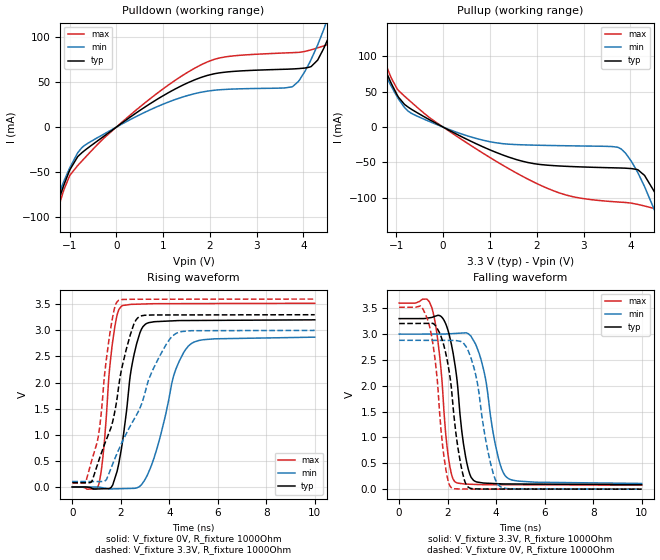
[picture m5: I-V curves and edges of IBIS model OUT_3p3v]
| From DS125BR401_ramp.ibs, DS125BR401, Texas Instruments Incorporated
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[Model]   OUT_3p3v
Model_type   Output
Polarity   Non-Inverting
Vmeas = 1.65
Vref = 0
Cref = 1pF
Rref = 1000000
|   typ   min   max
C_comp   1.124pF   1.078pF   1.193pF
[Voltage Range]   3.3   3   3.6
[Temperature Range]   25   105   -40
[Pullup Reference]   3.3   3   3.6
[Pulldown Reference]   0   0   0
[Power Clamp Reference]   3.3   3   3.6
[GND Clamp Reference]   0   0   0
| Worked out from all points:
|   slope of the pulldown table from 0 to 0.495 V, typ, clamps not added: 27.1 ohm
|   slope of the pullup table from 0 to 0.495 V, typ, clamps not added: 29.4 ohm
|   falling waveform, V_fixture 3.3V, R_fixture 1000Ohm: 20-80 % time 489ps typ, 628ps min, 396ps max; typ from 3.3 V to 0.088 V
|   rising waveform, V_fixture 0V, R_fixture 1000Ohm: 20-80 % time 569ps typ, 924ps min, 383ps max; typ from 0 V to 3.2 V
|   rising waveform, V_fixture 3.3V, R_fixture 1000Ohm: 20-80 % time 977ps typ, 1.62ns min, 558ps max; typ from 0.086 V to 3.3 V
|   falling waveform, V_fixture 0V, R_fixture 1000Ohm: 20-80 % time 529ps typ, 625ps min, 437ps max; typ from 3.21 V to 0 V
[Pulldown]
|   Voltage   I(typ)   I(min)   I(max)
-3.3V     -459.4mA   -422.5mA   -501.2mA
-1.459V   -116.1mA   -108.5mA   -127.1mA
-993.3mV  -47.53mA   -45.12mA   -53.69mA
-735.9mV  -28.5mA    -22.8mA    -37.74mA
699.6mV   25.33mA    18.74mA    30.68mA
1.947V    57.59mA    40.09mA    72.64mA
3.769V    64.77mA    45.19mA    82.94mA
4.165V    67.47mA    75.44mA    86.09mA
4.521V    97.97mA    121.6mA    92mA
4.63V     111.7mA    138.5mA    95.21mA
4.937V    155.3mA    189mA      130.7mA
6.59V     457.7mA    475.9mA    433.7mA
[Pullup]
|   Voltage   I(typ)   I(min)   I(max)
-3.3V     459.3mA    424.5mA    499.8mA
-1.696V   154.1mA    147.4mA    172mA
-1.488V   119.8mA    113.3mA    134mA
-1.102V   60.97mA    56.97mA    68.64mA
-686.4mV  25.61mA    19.85mA    35.57mA
838.2mV   -27.51mA   -18.27mA   -36.36mA
2.224V    -53.8mA    -25.87mA   -86.48mA
3.808V    -57.85mA   -31.15mA   -106.2mA
4.303V    -68.3mA    -84.12mA   -111.6mA
4.709V    -117.7mA   -149.4mA   -123.1mA
4.867V    -141.1mA   -176.1mA   -142mA
6.59V     -458.3mA   -473.1mA   -437.5mA
[Ramp]
R_load = 1000
|   typ   min   max
dV/dt_r   1.92113/5.67203e-10   1.72194/9.23251e-10   2.11128/3.82461e-10
dV/dt_f   1.9272/4.87269e-10   1.7334/6.24519e-10   2.11279/3.95506e-10
[Falling Waveform]
V_fixture = 3.3V
V_fixture_min = 3V
V_fixture_max = 3.6V
R_fixture = 1000Ohm
C_fixture = 0F
|   Time   V(typ)   V(min)   V(max)
0s        3.3V       3V         3.6V
1.343ns   3.323V     3V         3.517V
1.67ns    3.359V     3V         2.578V
2.024ns   3.058V     3.005V     643.3mV
2.333ns   2.307V     3.013V     133.6mV
2.655ns   868.9mV    3.022V     101.9mV
2.971ns   226.1mV    2.953V     94.39mV
3.406ns   124mV      2.457V     87.56mV
4.414ns   101mV      238.5mV    85.66mV
10ns      87.77mV    110.7mV    78.48mV
[Rising Waveform]
V_fixture = 0V
V_fixture_min = 0V
V_fixture_max = 0V
R_fixture = 1000Ohm
C_fixture = 0F
|   Time   V(typ)   V(min)   V(max)
0s        14.1uV     25uV       7.417uV
1.094ns   -37.31mV   -2.493mV   53.6mV
1.287ns   -34.4mV    -17.74mV   683.9mV
1.643ns   19.9mV     -36.92mV   2.705V
2.024ns   725.1mV    -32.31mV   3.462V
2.463ns   2.339V     -27mV      3.499V
3.021ns   3.12V      162.2mV    3.506V
4.226ns   3.185V     2.197V     3.512V
4.896ns   3.189V     2.743V     3.513V
10ns      3.202V     2.87V      3.519V
[Rising Waveform]
V_fixture = 3.3V
V_fixture_min = 3V
V_fixture_max = 3.6V
R_fixture = 1000Ohm
C_fixture = 0F
|   Time   V(typ)   V(min)   V(max)
0s        85.89mV    104.6mV    77.76mV
551.6ps   82.96mV    103.9mV    91.17mV
1.044ns   436.1mV    103.3mV    896.1mV
1.512ns   1.035V     257.4mV    2.818V
1.889ns   1.839V     688mV      3.566V
2.217ns   2.617V     1.011V     3.593V
2.623ns   3.196V     1.357V     3.596V
3.295ns   3.295V     2.218V     3.596V
4.226ns   3.296V     2.926V     3.597V
10ns      3.3V       2.999V     3.6V
[Falling Waveform]
|Gnd
V_fixture = 0V
V_fixture_min = 0V
V_fixture_max = 0V
R_fixture = 1000Ohm
C_fixture = 0F
|   Time   V(typ)   V(min)   V(max)
0s        3.205V     2.881V     3.52V
1.212ns   3.207V     2.879V     3.224V
1.512ns   3.154V     2.879V     2.384V
1.854ns   2.762V     2.879V     606.4mV
2.143ns   2.004V     2.878V     32.22mV
2.426ns   793.8mV    2.868V     5.088mV
2.743ns   107.9mV    2.769V     2.067mV
3.792ns   2.622mV    458.4mV    1.781mV
4.167ns   2.473mV    50.37mV    1.678mV
10ns      156uV      388uV      85.86uV
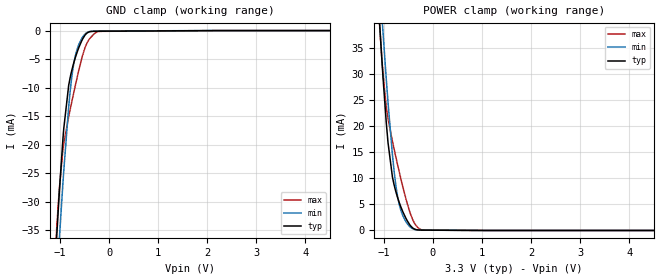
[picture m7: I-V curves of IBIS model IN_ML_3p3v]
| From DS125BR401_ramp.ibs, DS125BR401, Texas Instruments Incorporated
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[Model]   IN_ML_3p3v
Model_type   Input
Vinl = 0.8
Vinh = 2
|   typ   min   max
C_comp   1.124pF   1.078pF   1.193pF
[Voltage Range]   3.3   3   3.6
[Temperature Range]   25   105   -40
[Power Clamp Reference]   3.3   3   3.6
[GND Clamp Reference]   0   0   0
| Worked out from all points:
|   GND clamp passes 1 mA (typ) near -0.51 V on its own axis
|   POWER clamp passes 1 mA (typ) near -0.46 V on its own axis
[GND Clamp]
|   Voltage   I(typ)   I(min)   I(max)
-3.3V     -456.6mA   -420.7mA   -497.8mA
-1.073V   -36.74mA   -44.69mA   -35.17mA
-1.063V   -35.22mA   -43.26mA   -33.8mA
-1.013V   -27.98mA   -36.26mA   -27.56mA
-924mV    -17.09mA   -24.47mA   -19.77mA
-825mV    -9.616mA   -13.39mA   -15.11mA
-735.9mV  -6.128mA   -6.572mA   -11.47mA
-607.2mV  -2.745mA   -2.212mA   -6.56mA
-498.3mV  -870uA     -667.2uA   -3.166mA
-409.2mV  -233.1uA   -185.8uA   -1.561mA
-132mV    -108.9uA   -64.82uA   -127.1uA
6.59V     0A         0A         0A
[POWER Clamp]
|   Voltage   I(typ)   I(min)   I(max)
-3.3V     458.6mA    424.2mA    498.8mA
-1.092V   40.73mA    48.73mA    40.11mA
-1.023V   30.25mA    38.85mA    30.89mA
-953.7mV  21.11mA    29.5mA     23.97mA
-914.1mV  16.79mA    24.48mA    21.38mA
-825mV    10.27mA    14.52mA    17.12mA
-735.9mV  6.819mA    7.433mA    13.29mA
-607.2mV  3.469mA    2.707mA    8.151mA
-399.3mV  397.2uA    289.1uA    1.83mA
-270.6mV  81.86uA    77.85uA    291.1uA
-132mV    61.59uA    56.89uA    65.96uA
6.59V     0A         0A         0A
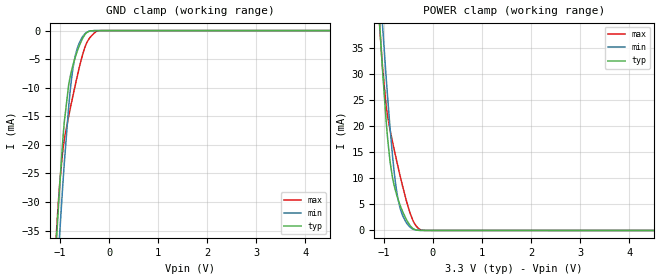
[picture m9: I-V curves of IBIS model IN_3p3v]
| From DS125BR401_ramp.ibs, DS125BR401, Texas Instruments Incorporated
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[Model]   IN_3p3v
Model_type   Input
Vinl = 0.8
Vinh = 2
|   typ   min   max
C_comp   1.124pF   1.078pF   1.193pF
[Voltage Range]   3.3   3   3.6
[Temperature Range]   25   105   -40
[Power Clamp Reference]   3.3   3   3.6
[GND Clamp Reference]   0   0   0
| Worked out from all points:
|   GND clamp passes 1 mA (typ) near -0.52 V on its own axis
|   POWER clamp passes 1 mA (typ) near -0.47 V on its own axis
[GND Clamp]
|   Voltage   I(typ)   I(min)   I(max)
-3.3V     -456.5mA   -420.6mA   -497.6mA
-1.073V   -36.62mA   -44.63mA   -35.03mA
-1.063V   -35.1mA    -43.2mA    -33.66mA
-1.013V   -27.86mA   -36.2mA    -27.42mA
-1.003V   -26.5mA    -34.83mA   -26.3mA
-914.1mV  -15.98mA   -23.18mA   -19.05mA
-825mV    -9.491mA   -13.32mA   -14.96mA
-735.9mV  -6.003mA   -6.506mA   -11.33mA
-607.2mV  -2.622mA   -2.143mA   -6.418mA
-409.2mV  -113.8uA   -117.8uA   -1.423mA
-132mV    -308.3nA   -375.5nA   -842.3nA
6.59V     0A         0A         0A
[POWER Clamp]
|   Voltage   I(typ)   I(min)   I(max)
-3.3V     458.5mA    424.1mA    498.7mA
-1.092V   40.66mA    48.66mA    40.03mA
-1.023V   30.18mA    38.79mA    30.81mA
-953.7mV  21.04mA    29.43mA    23.9mA
-874.5mV  13.27mA    19.72mA    19.3mA
-795.3mV  8.857mA    11.71mA    15.74mA
-735.9mV  6.746mA    7.367mA    13.21mA
-676.5mV  5.029mA    4.571mA    10.78mA
-607.2mV  3.398mA    2.641mA    8.079mA
-399.3mV  331.9uA    227.8uA    1.764mA
-171.6mV  8.81uA     8.05uA     13.85uA
6.59V     0A         0A         0A
